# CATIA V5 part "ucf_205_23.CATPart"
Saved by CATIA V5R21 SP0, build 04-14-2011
Part number: ucf_205_23
Bounding box of the stored display mesh (mm): x -18.5 to -12.5, y -17.2 to -11.2, z -2.853 to 2.853
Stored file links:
  C:\TPO v2\SharedFS\Outgoing\ucf_205_23.CATPart

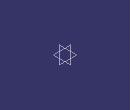
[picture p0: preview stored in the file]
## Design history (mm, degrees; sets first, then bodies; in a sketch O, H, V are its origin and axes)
AxisSystem1: origin (0, 0, 0), X (1, 0, 0), Y (0, 1, 0), Z (0, 0, 1)
Body1 "ucf_205_23" (main body)
  Solid1: solid without history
